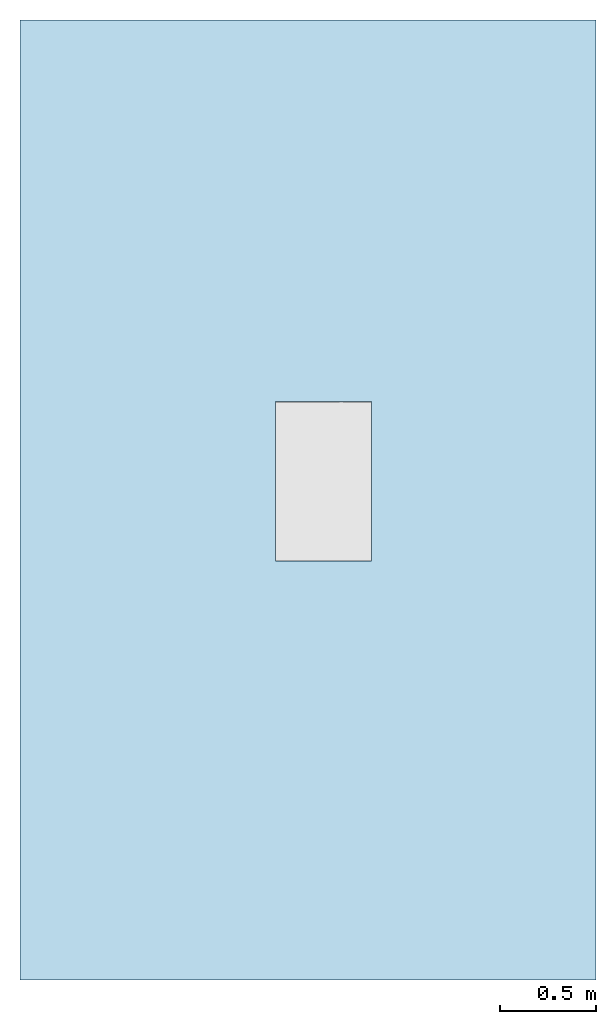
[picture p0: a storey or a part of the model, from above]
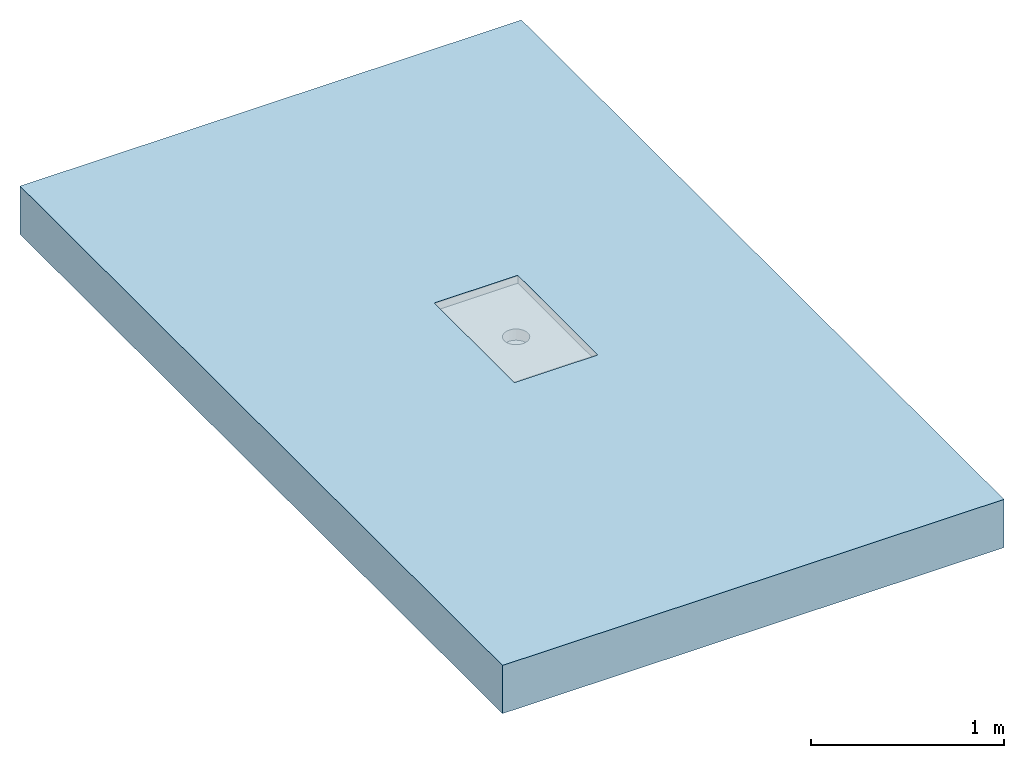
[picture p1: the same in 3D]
Properties of the parts of a building model (IFC2X3)

# File
Description: ViewDefinition [CoordinationView]
File name: Project Number
Time: 2016-11-22T11:18:51
Written by: The EXPRESS Data Manager Version 5.01.0100.02.64mod : 6 Jun 2012
Made in: 20130308_1515(x64) - Exporter 2014.0.2013.0308 - Default UI
Comment: STEP Physical File produced by: The EXPRESS Data Manager Version 5.01.0100.02.64mod : 6 Jun 2012 * Module: EDMstepFileFactory/EDMstandAlone * Creation date: Tue Nov 22 11:18:51 2016 * Host: IN-BLR-PC-0012 * Database: C:\Users\pakumar\AppData\Local\Temp\{E999853B-D2B7-4D47-9D25-CD18AFE5A7E7}\ifc * Database version: 5507 * Database creation date: Tue Nov 22 11:18:50 2016 * Schema: IFC2X3 * Model: DataRepository.ifc * Model creation date: Tue Nov 22 11:18:51 2016 * Header model: DataRepository.ifc_HeaderModel * Header model creation date: Tue Nov 22 11:18:51 2016 * EDMuser: sdai-user * EDMgroup: sdai-group * License ID and type: 5605 : Permanent license. Expiry date: * EDMstepFileFactory options: 020000

# IfcProject, Project Number
LongName: Project Name; Phase: Project Status

# IfcSite, Default
RefLatitude: 42, 21, 30, 344238; RefLongitude: -71, -3, -35, -194702; RefElevation: 0 mm

# IfcBuilding
Pset_BuildingCommon - NumberOfStoreys: 1
Other - Client Name: Owner; Project Status: Project Status; Project Name: Project Name; Project Address: Enter address here; Project Issue Date: Issue Date; Project Number: Project Number

# IfcBuildingStorey, Level 1
LongName: Level 1; Elevation: 0 mm
Constraints - Elevation Base: Project Base Point; Elevation: 0 mm
Graphics - Symbol at End 2 Default: yes; Line Weight: 1; Color: 0; Symbol: Level Head - Circle: Level Head - Circle; Line Pattern: Grid Line 1/2"; Symbol at End 1 Default: no
Dimensions - Computation Height: 0 mm
Identity Data - Structural: no; Name: Level 1; Building Story: yes

# IfcFlowTerminal: 416655 - Hygienic Standard Channel - with Gully 157 - 800mm LG - 500mm Wide, ACO Tray Channel - Hygienic - Standard - 500mm Wide:416655 - Hygienic Standard Channel - with Gully 157 - 800mm LG - 500mm Wide:702429
In: Level 1
Material: Stainless Steel AISI 304, Stainless Steel AISI 304 - Grating
Other - Hygienic Standard Channel - 1000mm LG - 500mm Wide: no; Number mesh: 17; Invert Depth Detail: 51.5 mm; Hygienic Standard Channel - 800mm LG - 500mm Wide: yes; Hygienic Standard Channel - 500mm LG - 500mm Wide: no; Flow: 0.0988811 m3/s; Spigot Outlets Channels: yes
Mechanical - System Classification: Sanitary
Construction - 416894 - 468 x 398mm - Mesh Grating - L15 - Stainless Steel 1.4301: no; 416830 - 468 x 398mm - Ladder Grating - R50 - Stainless Steel 1.4301: no; 416834 - 468 x 398mm - Ladder Grating - M125 - Stainless Steel 1.4301: no; 416872 - 468 x 499mm - Mesh Grating - L15 - Stainless Steel 1.4301: yes; 416832 - 468 x 499mm - Ladder Grating - M125 - Stainless Steel 1.4301: no; 416874 - 468 x 398mm - Mesh Grating - L15 - Stainless Steel 1.4301: no; 416892 - 468 x 499mm - Mesh Grating - L15 - Stainless Steel 1.4301: no; 416828 - 468 x 499mm - Ladder Grating - R50 - Stainless Steel 1.4301: no; Detail - Outlet 200: no; Grating: yes; Detail - Outlet 142mm: yes
Identity Data - Mark: 65; E-mail Technical: abdtechnical@aco.co.uk; E-mail Sales: abdcommercial@aco.co.uk; Watermarked With: BIM Manager Premium Suite.; Watermarked By: www.acobd.com; Watermark2: This file is water marked and users are prohibited to reproduce, adapt, distribute this information.; Watermark1: This file is the property of ACO Technologies PLC.; Manufacturer: ACO Building Drainage; Fax: +44 (0)1462 851490; Cost: 0; Telephone: +44 (0)1462 816666; Website: www.acobd.com; Address: ACO Business Centre, Caxton Road, Bedford, MK41 0LF
Constraints - Level: Level: Level 1
Phasing - Phase Created: New Construction
Pset_ManufacturerTypeInformation - Manufacturer: ACO Building Drainage
General - Maintenance guidelines: http://issuu.com/acobuildingdrainage/docs/aco_hygiene_first_catalogue/17?e=0; Channel Recycled material content: 20 - 30 %; Channel Recyclable: Fully recyclable; Channel Material: Stainless steel 1.4301 (EN 10088); Foul air trap seal Material: NBR; Foul air trap Recyclable: Fully recyclable; Installation guidelines: http://issuu.com/acobuildingdrainage/docs/aco_hygiene_first_catalogue/17?e=0; Weight (Kg): 8.4; Price: POA - contact ACO; Foul air trap Recycled material content: 0%; Channel Dimension: 500 x 830; Channel Colour: passivated stainless steel surface ( matt grey); Product Range: ACO Hygiene First; Load Class: A15 - C250 (EN 1253); Foul air trap seal Colour: Black; Outlet Diameter (mm): 142; Product Description: ACO Hygiene First Standard Kitchen Tray Channel 500 x 830 / 142 Dia Outlet & Foul Air Trap; Product Code: 416655; Product Standard: EN 1253 / EN 1672 / EN ISO 14159; Product Type: Standard Kitchen Tray Channel
Dimensions - End Connection Plate Start: -770 mm; Depth: 29 mm; End Connection Plate End: -800 mm; Length Channel: -770 mm; End Plate: 800 mm; x: -815 mm; Outside Outlet Rad: 71 mm; Outlet: 142 mm; Grating Void Cut Length: 500 mm; Endplate Position: 800 mm; Inside Outlet Rad: 66 mm; Number of gratings: 2; Grating Length: 499 mm; Spigot Distance: 400 mm; Invert Depth: 50 mm; Floor Cut Void Height: 62.8 mm; Grating Height: 21 mm
Model Properties - Grating Product Code 416830: Load Class R 50 (EN 1253) - Ladder Grate - Stainless steel 1.4301 (EN 10088) - 468 x 398 - 12.5kg; Grating Product Code 416828: N/A; Grating Product Code 416894: Load Class L 15 (EN 1253) - Mesh Grate - Stainless steel 1.4301 (EN 10088) - 468 x 398 - 5.2kg; Grating Product Code 416832: N/A; Grating Product Code 416874: Load Class L 15 (EN 1253) - Mesh Grate - Stainless steel 1.4301 (EN 10088) - 468 x 398 - 5kg; Grating Product Code 416834: Load Class M 125 (EN 1253) - Ladder Grate - Stainless steel 1.4301 (EN 10088) - 468 x 398 - 12.5kg; Grating Product Code 416872: N/A; Grating Product Code 416892: N/A

# IfcOpeningElement: Recess
In: Level 1
Phasing - Phase Created: New Construction
Dimensions - Area: 161.459 ft2; Thickness: 304.8 mm; Volume: 160.687 ft3; Perimeter: 16000 mm
Constraints - Room Bounding: yes; Level: Level: Level 1; Related to Mass: no; Height Offset From Level: 0 mm
Structural - Enable Analytical Model: no; Structural: no
Graphics - Coarse Scale Fill Color: 0
Analytical Properties - Absorptance: 0.7; Roughness: 3
Construction - Default Thickness: 304.8 mm; Function: Interior
Identity Data - Assembly Code: B1010; Assembly Description: Floor Construction

# IfcSlab: Floor:Generic - 12", Floor:Generic - 12":184145
In: Level 1
PredefinedType: FLOOR; Material: Default Floor 304.8 mm
Phasing - Phase Created: New Construction
Dimensions - Area: 161.459 ft2; Thickness: 304.8 mm; Volume: 160.687 ft3; Perimeter: 16000 mm
Constraints - Room Bounding: yes; Level: Level: Level 1; Related to Mass: no; Height Offset From Level: 0 mm
Structural - Enable Analytical Model: no; Structural: no
Pset_SlabCommon - Reference: Generic - 12"; IsExternal: no; LoadBearing: yes
Graphics - Coarse Scale Fill Color: 0
Analytical Properties - Absorptance: 0.7; Roughness: 3
Construction - Default Thickness: 304.8 mm; Function: Interior
Identity Data - Assembly Code: B1010; Assembly Description: Floor Construction
